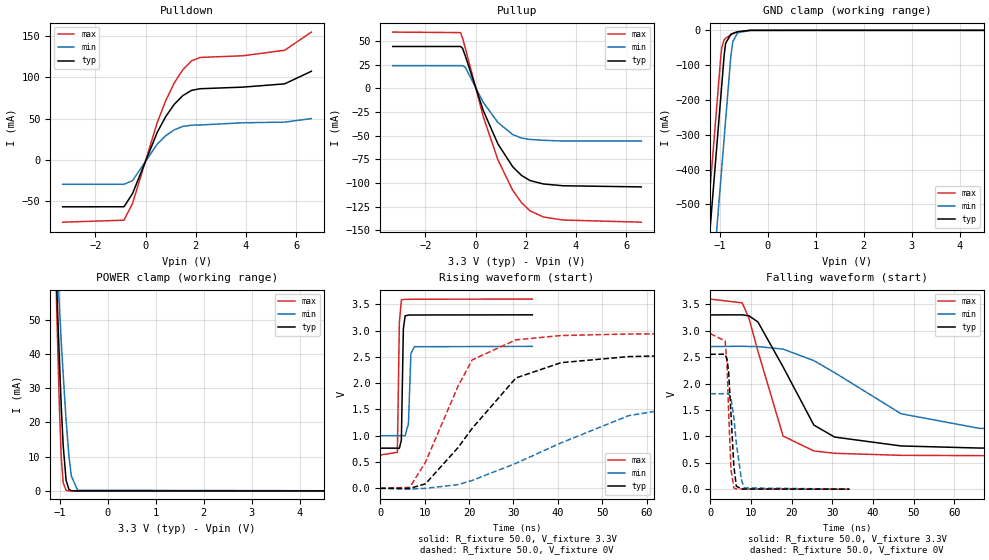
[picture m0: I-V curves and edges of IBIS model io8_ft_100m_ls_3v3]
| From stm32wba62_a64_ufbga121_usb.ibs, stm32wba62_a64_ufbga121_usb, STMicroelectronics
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[Model]   io8_ft_100m_ls_3v3
Model_type I/O
Polarity   Non-Inverting
Enable   Active-Low
| CAP_THRESHOLD on pad IOFT is "UDTCAPC" :
| Rising=30.0% of vddiom   Falling=70.0% of vddiom
| C_comp min and max val. don't necessarily correlate with the min and max pvt
| but are the smallest and greatest pad capacitance found.
| var   typ   min   max
C_comp   3.79770pF  3.69233pF  3.85115pF
|C_comp_pullup   2.35181pF  2.17395pF  2.43299pF
|C_comp_pulldown   1.44589pF  1.51838pF  1.41817pF
Vinl = 1.35V
Vinh = 1.8V
Vmeas = 1.65V   | Reference voltage for timing measurements
Cref  = 50.0pF   | Timing specification test load capacitance value
Rref  = 1.0MOhm   | Timing specification test load resistance value
Vref  = 1.815V   | Timing specification test load voltage
[Model Spec]
| TIME_THRESHOLD on pin ZIV11 is "CMOS" :
| Rising=50.0% of vdd   Falling=50.0% of vdd
Vinl 1.29050V 1.08050V 1.37650V
Vinh 1.79850V 1.52050V 1.90250V
| variable   typ   min   max
[Temperature Range] 25.0 140.0 -40.0
| variable   typ   min   max
[Voltage Range] 3.3V 2.7V 3.6V
| variable   typ   min   max
[POWER Clamp Reference] 3.3V 2.7V 3.6V
| variable   typ   min   max
[GND Clamp Reference] 0V 0V 0V
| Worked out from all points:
|   slope of the pulldown table from 0 to 0.495 V, typ, clamps not added: 14 ohm
|   slope of the pullup table from 0 to 0.495 V, typ, clamps not added: 13.8 ohm
|   GND clamp passes 1 mA (typ) near -0.51 V on its own axis
|   POWER clamp passes 1 mA (typ) near -0.83 V on its own axis
|   rising waveform, R_fixture 50.0, V_fixture 3.3V: 20-80 % time 256ps typ, 344ps min, 240ps max; typ from 0.764 V to 3.3 V
|   falling waveform, R_fixture 50.0, V_fixture 3.3V: 20-80 % time 10.1ns typ, 23.2ns min, 6.36ns max; typ from 3.3 V to 0.764 V
|   rising waveform, R_fixture 50.0, V_fixture 0V: 20-80 % time 14.6ns typ, 31.4ns min, 9.34ns max; typ from 0 V to 2.55 V
|   falling waveform, R_fixture 50.0, V_fixture 0V: 20-80 % time 1.02ns typ, 1.58ns min, 820ps max; typ from 2.55 V to 0 V
[POWER Clamp]
-3.3V     1.123A     753mA      1.645A
-1.09V    69.42mA    75.17mA    67.14mA
-1.08V    65.31mA    72.42mA    61.23mA
-1.06V    57.23mA    66.98mA    49.77mA
-1.01V    38.06mA    53.68mA    24.29mA
-970mV    24.36mA    43.46mA    9.575mA
-930mV    13.06mA    33.74mA    2.352mA
-870mV    3.065mA    20.56mA    165.9uA
-810mV    418.4uA    10.06mA    10.3uA
-760mV    69.41uA    4.321mA    1.009uA
-630mV    611.5nA    197uA      2.727nA
6.6V      0A         0A         0A
[GND Clamp]
-3.3V     -4.134A    -4.372A    -4.018A
-1.59V    -1.227A    -1.465A    -1.111A
-1.25V    -648.9mA   -886.9mA   -533mA
-980mV    -189.9mA   -427.9mA   -74mA
-960mV    -155.9mA   -393.9mA   -48.8mA
-910mV    -70.86mA   -308.9mA   -27.2mA
-880mV    -37.23mA   -257.9mA   -22.76mA
-770mV    -11.28mA   -71.59mA   -12.95mA
-730mV    -8.709mA   -32.74mA   -10.07mA
-630mV    -4.122mA   -6.943mA   -4.354mA
-370mV    -42.68uA   -212.2uA   -13.03uA
6.6V      2.311nA    506.4nA    1.057nA
| variable   typ   min   max
[Pullup Reference] 3.3V 2.7V 3.6V
| variable   typ   min   max
[Pulldown Reference] 0V 0V 0V
[Pullup]
-3.3V     44.28mA    24.03mA    59.51mA
-600mV    44.28mA    24.03mA    58.97mA
-520mV    42.47mA    24.03mA    53.36mA
-410mV    34.41mA    22.34mA    42.54mA
310mV     -23.64mA   -14.94mA   -30.17mA
890mV     -58.72mA   -36.07mA   -75.54mA
1.48V     -82.86mA   -48.82mA   -107.8mA
1.83V     -91.99mA   -52.47mA   -120.8mA
2.17V     -97.42mA   -53.93mA   -129.4mA
2.7V      -101mA     -54.85mA   -135.9mA
3.48V     -102.9mA   -55.62mA   -139.1mA
6.6V      -104.1mA   -55.62mA   -141.4mA
[Pulldown]
-3.3V     -56.7mA    -29.42mA   -75.36mA
-860mV    -56.67mA   -29.42mA   -72.94mA
-520mV    -40.69mA   -25.01mA   -52.64mA
460mV     33.25mA    19.09mA    44.92mA
800mV     52.54mA    29.36mA    71.75mA
1.14V     67.41mA    36.49mA    93.2mA
1.48V     77.97mA    40.67mA    109.3mA
1.83V     84.38mA    42.18mA    120.1mA
2.17V     86.37mA    42.45mA    124.3mA
3.88V     88.31mA    45.1mA     126.3mA
5.54V     92.28mA    45.89mA    133mA
6.6V      107.5mA    50.2mA     155mA
[Ramp]
dV/dt_r 1.53258V/14.59623ns 1.08436V/31.15672ns 1.76673V/9.28636ns
dV/dt_f 1.52157V/9.99328ns 1.01888V/23.02337ns 1.77971V/6.34203ns
R_load = 50.0
| Removed startup time: 0s 0s 0s  .
| Removed end time: 34.25ns.
[Rising Waveform]
R_fixture   = 50.0
V_fixture   = 3.3V
V_fixture_min = 2.7V
V_fixture_max = 3.6V
0s        764mV      1.002V     633.8mV
3.85ns    764.1mV    1.002V     684.4mV
4.3ns     762.1mV    1.002V     3.159V
4.75ns    918mV      1.002V     3.582V
5.2ns     3.037V     1.001V     3.592V
5.6ns     3.281V     999.5mV    3.594V
6.35ns    3.295V     1.236V     3.595V
6.9ns     3.296V     2.567V     3.596V
7.7ns     3.297V     2.694V     3.597V
34.25ns   3.3V       2.7V       3.6V
| Removed startup time: 0s 0s 0s  .
| Removed end time: 249.25ns.
[Falling Waveform]
R_fixture   = 50.0
V_fixture   = 3.3V
V_fixture_min = 2.7V
V_fixture_max = 3.6V
0s        3.3V       2.7V       3.6V
7.85ns    3.301V     2.706V     3.528V
9.5ns     3.283V     2.702V     3.238V
11.7ns    3.167V     2.7V       2.615V
17.9ns    2.314V     2.652V     1.005V
25.45ns   1.214V     2.434V     723.6mV
30.55ns   986.8mV    2.207V     679.6mV
46.9ns    818.4mV    1.428V     640.9mV
66.15ns   778.7mV    1.151V     635.1mV
249.3ns   764mV      1.002V     633.8mV
| Removed startup time: 0s 0s 0s  .
| Removed end time: 249.25ns.
[Rising Waveform]
R_fixture   = 50.0
V_fixture   = 0V
V_fixture_min = 0V
V_fixture_max = 0V
0s        20.8nV     123.7nV    58.33nV
6.65ns    -1.077mV   -15.72mV   19.03mV
10.2ns    86.05mV    -152.1uV   501.3mV
17.55ns   778.3mV    71.33mV    1.949V
20.7ns    1.141V     150.7mV    2.443V
30.55ns   2.099V     475.2mV    2.824V
40.7ns    2.39V      864.8mV    2.906V
55.95ns   2.506V     1.382V     2.936V
76.3ns    2.543V     1.666V     2.943V
249.3ns   2.554V     1.807V     2.945V
| Removed startup time: 0s 0s 0s  .
| Removed end time: 34.2ns.
[Falling Waveform]
R_fixture   = 50.0
V_fixture   = 0V
V_fixture_min = 0V
V_fixture_max = 0V
0s        2.554V     1.807V     2.945V
3.65ns    2.556V     1.807V     2.806V
4.1ns     2.464V     1.807V     2.391V
4.5ns     2.235V     1.809V     1.481V
5.1ns     1.408V     1.72V      360.2mV
5.8ns     430.2mV    1.35V      22.83mV
6.4ns     56.84mV    872.8mV    5.915mV
7.7ns     3.382mV    159.6mV    3.041mV
8.4ns     2.359mV    23.77mV    2.944mV
34.2ns    159.7uV    246.9uV    121.6uV
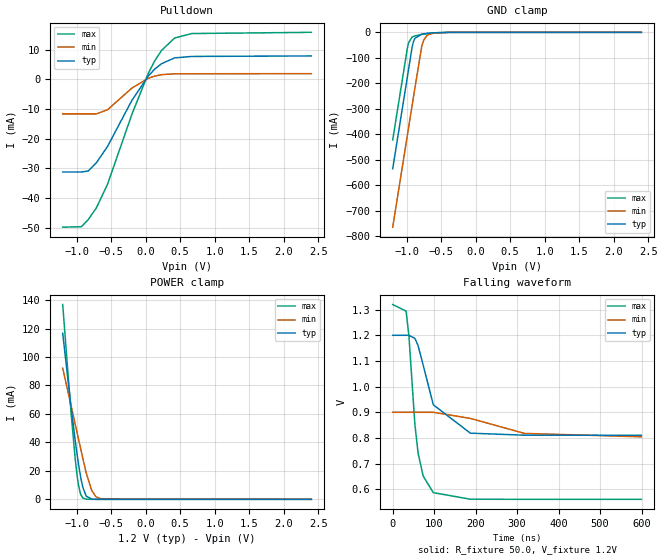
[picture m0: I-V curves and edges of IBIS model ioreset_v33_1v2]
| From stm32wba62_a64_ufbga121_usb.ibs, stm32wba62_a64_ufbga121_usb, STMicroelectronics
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[Model]   ioreset_v33_1v2
Model_type I/O_open_drain
Polarity   Inverting
Enable   Active-Low
| CAP_THRESHOLD on pad IOFT is "UDTCAPC" :
| Rising=30.0% of vddiom   Falling=70.0% of vddiom
| C_comp min and max val. don't necessarily correlate with the min and max pvt
| but are the smallest and greatest pad capacitance found.
| var   typ   min   max
C_comp   2.08973pF  1.99772pF  2.14571pF
|C_comp_pulldown   2.08973pF  1.99772pF  2.14571pF
Vinl = 450.0mV
Vinh = 660.0mV
Vmeas = 600.0mV   | Reference voltage for timing measurements
Cref  = 50.0pF   | Timing specification test load capacitance value
Rref  = 1.0MOhm   | Timing specification test load resistance value
Vref  = 660.0mV   | Timing specification test load voltage
[Model Spec]
| TIME_THRESHOLD on pin ZIV33M is "CMOS" :
| Rising=50.0% of vddiom   Falling=50.0% of vddiom
Vinl 439.50000mV 333.50000mV 484.50000mV
Vinh 749.50000mV 546.50000mV 833.50000mV
| variable   typ   min   max
[Temperature Range] 25.0 140.0 -40.0
| variable   typ   min   max
[Voltage Range] 1.2V 900.0mV 1.32V
| variable   typ   min   max
[POWER Clamp Reference] 1.2V 900.0mV 1.32V
| variable   typ   min   max
[GND Clamp Reference] 0V 0V 0V
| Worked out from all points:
|   slope of the pulldown table from 0 to 0.18 V, typ, clamps not added: 40.7 ohm
|   GND clamp passes 1 mA (typ) near -0.54 V on its own axis
|   POWER clamp passes 1 mA (typ) near -0.83 V on its own axis
|   falling waveform, R_fixture 50.0, V_fixture 1.2V: 20-80 % time 43.1ns typ, 109ns min, 23.8ns max; typ from 1.2 V to 0.81 V
[POWER Clamp]
-1.2V     116.7mA    92.13mA    136.9mA
-1.09V    69.42mA    68.21mA    67.14mA
-1.02V    41.75mA    52.99mA    28.91mA
-990mV    30.98mA    46.47mA    16.09mA
-970mV    24.36mA    42.12mA    9.575mA
-940mV    15.59mA    35.6mA     3.485mA
-910mV    8.693mA    29.07mA    1.01mA
-860mV    2.259mA    18.59mA    104.6uA
-780mV    143.1uA    6.246mA    2.554uA
-720mV    16.22uA    1.846mA    157nA
-650mV    1.266uA    330.3uA    6.085nA
2.4V      0A         0A         0A
[GND Clamp]
-1.2V     -535.9mA   -765.1mA   -422.7mA
-990mV    -178.9mA   -408.1mA   -65.71mA
-970mV    -144.9mA   -374.1mA   -40.56mA
-920mV    -59.9mA    -289.1mA   -18.76mA
-900mV    -37.03mA   -255.1mA   -15.96mA
-880mV    -24.1mA    -221.1mA   -14.14mA
-780mV    -7.18mA    -55.54mA   -8.407mA
-750mV    -5.876mA   -29.7mA    -7.021mA
-700mV    -4.221mA   -11.4mA    -4.959mA
-610mV    -2.051mA   -3.099mA   -2.141mA
-390mV    -46.32uA   -186.9uA   -16.64uA
2.4V      270.9pA    22.22nA    172.7pA
| variable   typ   min   max
[Pullup Reference] 1.2V 900.0mV 1.32V
| variable   typ   min   max
[Pulldown Reference] 0V 0V 0V
[Pulldown]
-1.2V     -31.18mA   -11.6mA    -49.76mA
-930mV    -31.18mA   -11.6mA    -49.61mA
-830mV    -30.84mA   -11.6mA    -47.23mA
-710mV    -28.02mA   -11.6mA    -43.16mA
-550mV    -22.53mA   -10.19mA   -35.26mA
-200mV    -7.132mA   -2.956mA   -11.87mA
40mV      1.168mA    404.3uA    2.087mA
130mV     3.407mA    1.114mA    6.168mA
230mV     5.287mA    1.605mA    9.74mA
420mV     7.262mA    1.887mA    13.95mA
670mV     7.748mA    1.913mA    15.46mA
2.4V      7.914mA    1.945mA    15.87mA
[Ramp]
dV/dt_r 228.34265mV/749.05147ps 57.55963mV/2.00538ns 447.33011mV/422.59932ps
dV/dt_f 233.72226mV/42.9222ns 57.27818mV/108.32263ns 455.54216mV/23.64768ns
R_load = 50.0
| Removed startup time: 0s 0s 0s  .
| Removed end time: 289.99us.
|[Rising Waveform]
|R_fixture   = 50.0
|V_fixture   = 1.2V
|V_fixture_min = 900.0mV
|V_fixture_max = 1.32V
|  0s  810.46292mV  804.06740mV  560.76310mV
|  10.0ns  810.46288mV  804.06677mV  560.76310mV
|  20.0ns  810.46288mV  804.06675mV  560.76310mV
|  5.92us  810.46288mV  804.06675mV  560.76310mV
|  11.84us  810.46288mV  804.06675mV  560.76310mV
|  17.76us  810.46288mV  804.06675mV  560.76310mV
|  23.67us  810.46288mV  804.06675mV  560.76310mV
|  29.59us  810.46288mV  804.06675mV  560.76310mV
|  35.51us  810.46288mV  804.06675mV  560.76310mV
|  41.43us  810.46288mV  804.06675mV  560.76310mV
|  47.35us  810.46288mV  804.06675mV  560.76310mV
|  53.27us  810.46288mV  804.06675mV  560.76310mV
|  58.7us  810.46288mV  804.06675mV  560.76310mV
|  58.71us  810.46288mV  804.06675mV  560.76313mV
|  58.72us  810.46288mV  804.06675mV  558.51331mV
|  58.73us  810.46288mV  804.06675mV  1.31992V
|  58.74us  810.46288mV  804.06675mV  1.31997V
|  58.76us  810.46288mV  804.06675mV  1.31999V
|  58.81us  810.46288mV  804.06675mV  1.31999V
|  58.82us  810.46288mV  804.06675mV  1.32000V
|  59.18us  810.46288mV  804.06675mV  1.32000V
|  65.1us  810.46288mV  804.06675mV  1.32000V
|  71.02us  810.46288mV  804.06675mV  1.32000V
|  76.94us  810.46288mV  804.06675mV  1.32000V
|  82.86us  810.46288mV  804.06675mV  1.32000V
|  88.78us  810.46288mV  804.06675mV  1.32000V
|  93.02us  810.46290mV  804.06675mV  1.32000V
|  93.03us  810.46306mV  804.06675mV  1.32000V
|  93.04us  805.94414mV  804.06675mV  1.32000V
|  93.05us  1.19989V  804.06675mV  1.32000V
|  93.06us  1.19996V  804.06675mV  1.32000V
|  93.07us  1.19998V  804.06675mV  1.32000V
|  93.08us  1.19998V  804.06675mV  1.32000V
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[Falling Waveform]
R_fixture   = 50.0
V_fixture   = 1.2V
V_fixture_min = 900.0mV
V_fixture_max = 1.32V
0s        1.2V       900mV      1.32V
32.35ns   1.2V       900mV      1.294V
39.2ns    1.2V       900mV      1.195V
53.45ns   1.188V     900mV      852.9mV
61.15ns   1.16V      900mV      741.3mV
73.4ns    1.084V     900mV      651.5mV
97.85ns   929.2mV    900mV      586.9mV
187.3ns   818.6mV    876.1mV    561.2mV
318ns     810.7mV    817.6mV    560.8mV
599.3ns   810.5mV    804.5mV    560.8mV
